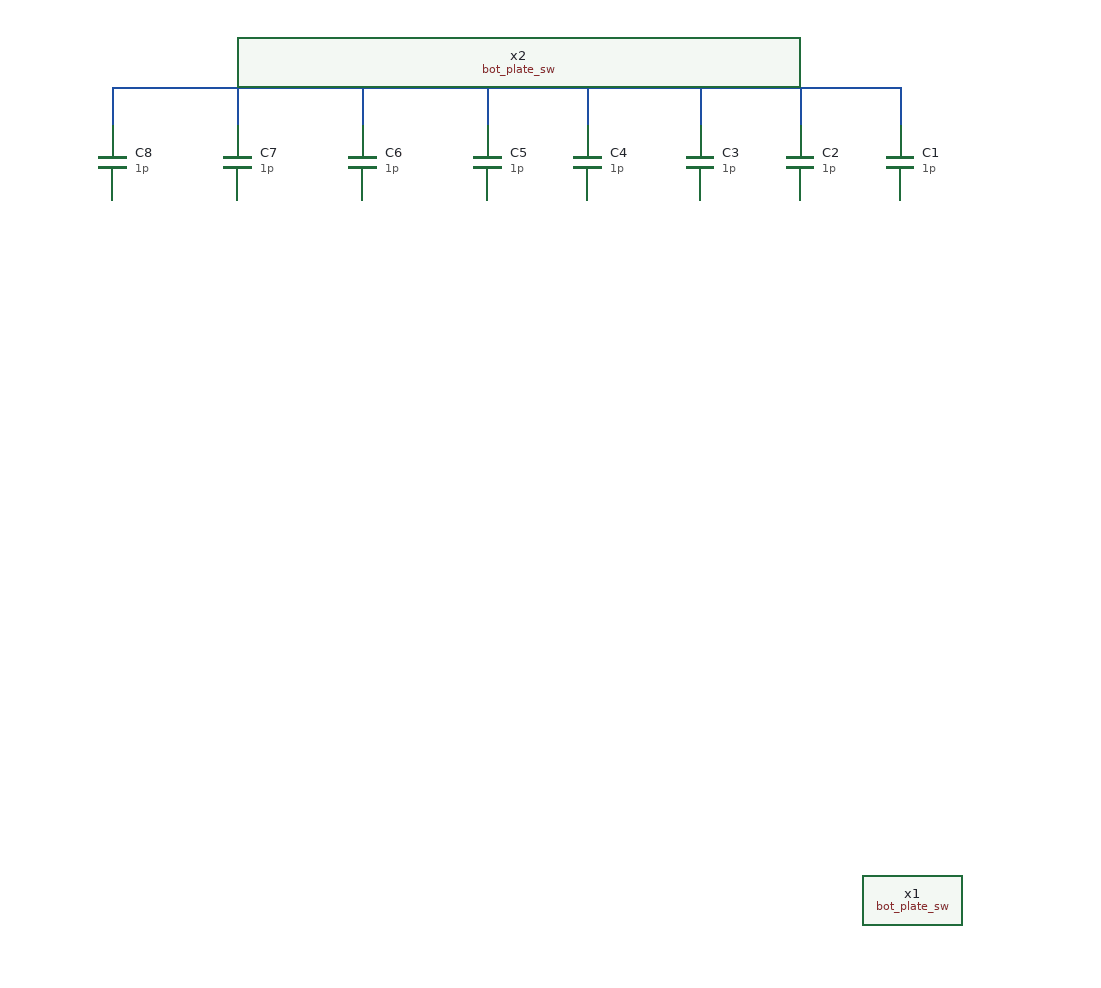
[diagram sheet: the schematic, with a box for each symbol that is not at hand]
v {xschem version=3.4.6 file_version=1.2}
G {}
K {}
V {}
S {}
E {}
N 1750 -1190 1750 -1160 {lab=#net1}
N 1750 -1190 2380 -1190 {lab=#net1}
N 2380 -1190 2380 -1160 {lab=#net1}
N 2300 -1190 2300 -1160 {lab=#net1}
N 2220 -1190 2220 -1160 {lab=#net1}
N 2130 -1190 2130 -1160 {lab=#net1}
N 2050 -1190 2050 -1160 {lab=#net1}
N 1950 -1190 1950 -1160 {lab=#net1}
N 1850 -1190 1850 -1160 {lab=#net1}
C {bot_plate_sw.sym} 2390 -540 3 0 {name=x1}
C {bot_plate_sw.sym} 2070 -590 3 0 {name=x2}
C {devices/capa.sym} 2380 -1130 0 0 {name=C1
m=1
value=1p
footprint=1206
device="ceramic capacitor"}
C {devices/capa.sym} 2300 -1130 0 0 {name=C2
m=1
value=1p
footprint=1206
device="ceramic capacitor"}
C {devices/capa.sym} 2220 -1130 0 0 {name=C3
m=1
value=1p
footprint=1206
device="ceramic capacitor"}
C {devices/capa.sym} 2130 -1130 0 0 {name=C4
m=1
value=1p
footprint=1206
device="ceramic capacitor"}
C {devices/capa.sym} 2050 -1130 0 0 {name=C5
m=1
value=1p
footprint=1206
device="ceramic capacitor"}
C {devices/capa.sym} 1950 -1130 0 0 {name=C6
m=1
value=1p
footprint=1206
device="ceramic capacitor"}
C {devices/capa.sym} 1850 -1130 0 0 {name=C7
m=1
value=1p
footprint=1206
device="ceramic capacitor"}
C {devices/capa.sym} 1750 -1130 0 0 {name=C8
m=1
value=1p
footprint=1206
device="ceramic capacitor"}
